###############################################################
#  Generated by:      Cadence Innovus 21.15-s110_1
#  OS:                Linux x86_64(Host ID A17)
#  Generated on:      Sun May  3 01:25:29 2026
#  Design:            Single_Cycle_Core
#  Command:           write_lef_abstract Single_Cycle_Core.lef -5.8
###############################################################

VERSION 5.8 ;

BUSBITCHARS "[]" ;
DIVIDERCHAR "/" ;

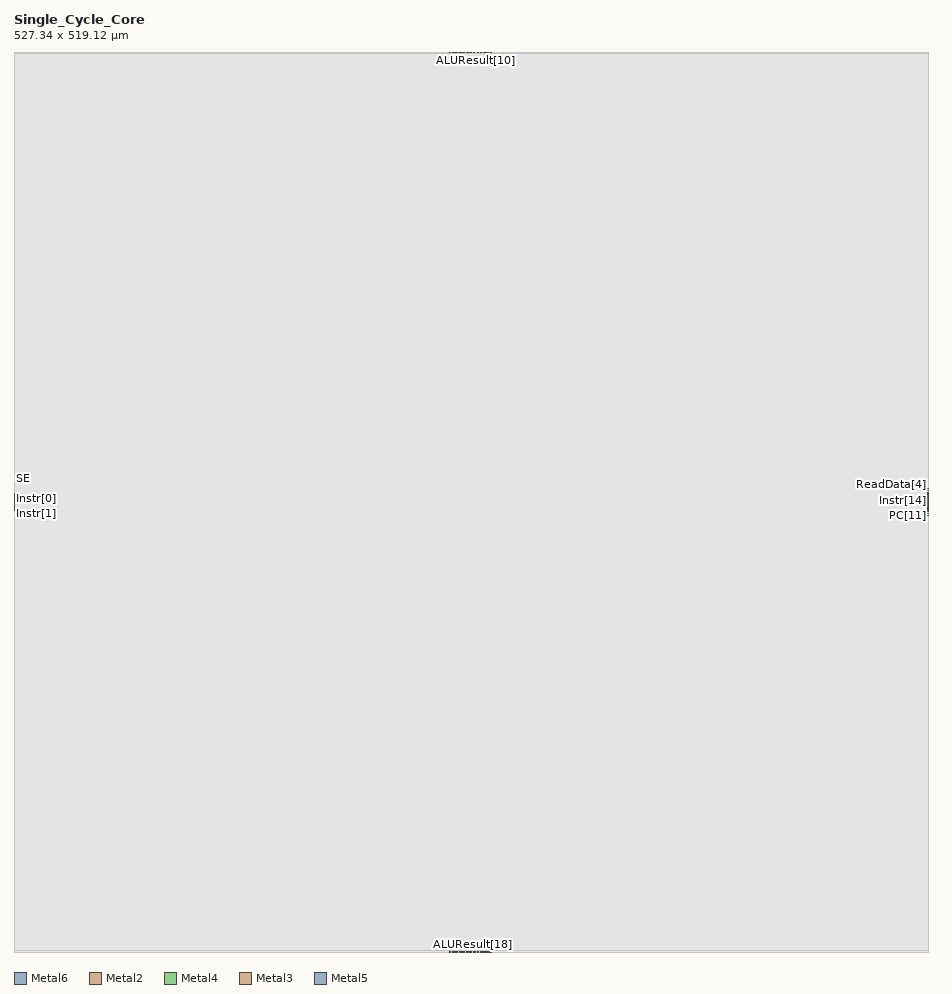
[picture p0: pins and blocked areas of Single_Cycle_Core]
MACRO Single_Cycle_Core
  CLASS BLOCK ;
  SIZE 527.340000 BY 519.120000 ;
  FOREIGN Single_Cycle_Core 0.000000 0.000000 ;
  ORIGIN 0 0 ;
  SYMMETRY X Y R90 ;
  PIN clk
    DIRECTION INPUT ;
    USE SIGNAL ;
    PORT
      LAYER Metal6 ;
        RECT 251.240000 518.680000 251.680000 519.120000 ;
    END
  END clk
  PIN reset
    DIRECTION INPUT ;
    USE SIGNAL ;
    PORT
      LAYER Metal6 ;
        RECT 251.240000 0.000000 251.680000 0.440000 ;
    END
  END reset
  PIN Instr[31]
    DIRECTION INPUT ;
    USE SIGNAL ;
    PORT
      LAYER Metal2 ;
        RECT 259.570000 518.840000 259.850000 519.120000 ;
    END
  END Instr[31]
  PIN Instr[30]
    DIRECTION INPUT ;
    USE SIGNAL ;
    PORT
      LAYER Metal4 ;
        RECT 259.570000 518.840000 259.850000 519.120000 ;
    END
  END Instr[30]
  PIN Instr[29]
    DIRECTION INPUT ;
    USE SIGNAL ;
    PORT
      LAYER Metal2 ;
        RECT 259.570000 0.000000 259.850000 0.280000 ;
    END
  END Instr[29]
  PIN Instr[28]
    DIRECTION INPUT ;
    USE SIGNAL ;
    PORT
      LAYER Metal4 ;
        RECT 259.570000 0.000000 259.850000 0.280000 ;
    END
  END Instr[28]
  PIN Instr[27]
    DIRECTION INPUT ;
    USE SIGNAL ;
    PORT
      LAYER Metal3 ;
        RECT 0.000000 259.420000 0.280000 259.700000 ;
    END
  END Instr[27]
  PIN Instr[26]
    DIRECTION INPUT ;
    USE SIGNAL ;
    PORT
      LAYER Metal5 ;
        RECT 0.000000 259.420000 0.280000 259.700000 ;
    END
  END Instr[26]
  PIN Instr[25]
    DIRECTION INPUT ;
    USE SIGNAL ;
    PORT
      LAYER Metal3 ;
        RECT 527.060000 259.420000 527.340000 259.700000 ;
    END
  END Instr[25]
  PIN Instr[24]
    DIRECTION INPUT ;
    USE SIGNAL ;
    PORT
      LAYER Metal5 ;
        RECT 527.060000 259.420000 527.340000 259.700000 ;
    END
  END Instr[24]
  PIN Instr[23]
    DIRECTION INPUT ;
    USE SIGNAL ;
    PORT
      LAYER Metal6 ;
        RECT 259.160000 518.680000 259.600000 519.120000 ;
    END
  END Instr[23]
  PIN Instr[22]
    DIRECTION INPUT ;
    USE SIGNAL ;
    PORT
      LAYER Metal6 ;
        RECT 259.160000 0.000000 259.600000 0.440000 ;
    END
  END Instr[22]
  PIN Instr[21]
    DIRECTION INPUT ;
    USE SIGNAL ;
    PORT
      LAYER Metal3 ;
        RECT 0.000000 258.300000 0.280000 258.580000 ;
    END
  END Instr[21]
  PIN Instr[20]
    DIRECTION INPUT ;
    USE SIGNAL ;
    PORT
      LAYER Metal3 ;
        RECT 0.000000 260.540000 0.280000 260.820000 ;
    END
  END Instr[20]
  PIN Instr[19]
    DIRECTION INPUT ;
    USE SIGNAL ;
    PORT
      LAYER Metal5 ;
        RECT 0.000000 258.300000 0.280000 258.580000 ;
    END
  END Instr[19]
  PIN Instr[18]
    DIRECTION INPUT ;
    USE SIGNAL ;
    PORT
      LAYER Metal5 ;
        RECT 0.000000 260.540000 0.280000 260.820000 ;
    END
  END Instr[18]
  PIN Instr[17]
    DIRECTION INPUT ;
    USE SIGNAL ;
    PORT
      LAYER Metal3 ;
        RECT 527.060000 258.300000 527.340000 258.580000 ;
    END
  END Instr[17]
  PIN Instr[16]
    DIRECTION INPUT ;
    USE SIGNAL ;
    PORT
      LAYER Metal3 ;
        RECT 527.060000 260.540000 527.340000 260.820000 ;
    END
  END Instr[16]
  PIN Instr[15]
    DIRECTION INPUT ;
    USE SIGNAL ;
    PORT
      LAYER Metal5 ;
        RECT 527.060000 258.300000 527.340000 258.580000 ;
    END
  END Instr[15]
  PIN Instr[14]
    DIRECTION INPUT ;
    USE SIGNAL ;
    PORT
      LAYER Metal5 ;
        RECT 527.060000 260.540000 527.340000 260.820000 ;
    END
  END Instr[14]
  PIN Instr[13]
    DIRECTION INPUT ;
    USE SIGNAL ;
    PORT
      LAYER Metal2 ;
        RECT 258.250000 518.840000 258.530000 519.120000 ;
    END
  END Instr[13]
  PIN Instr[12]
    DIRECTION INPUT ;
    USE SIGNAL ;
    PORT
      LAYER Metal2 ;
        RECT 268.810000 518.840000 269.090000 519.120000 ;
    END
  END Instr[12]
  PIN Instr[11]
    DIRECTION INPUT ;
    USE SIGNAL ;
    PORT
      LAYER Metal4 ;
        RECT 258.250000 518.840000 258.530000 519.120000 ;
    END
  END Instr[11]
  PIN Instr[10]
    DIRECTION INPUT ;
    USE SIGNAL ;
    PORT
      LAYER Metal4 ;
        RECT 268.810000 518.840000 269.090000 519.120000 ;
    END
  END Instr[10]
  PIN Instr[9]
    DIRECTION INPUT ;
    USE SIGNAL ;
    PORT
      LAYER Metal2 ;
        RECT 258.250000 0.000000 258.530000 0.280000 ;
    END
  END Instr[9]
  PIN Instr[8]
    DIRECTION INPUT ;
    USE SIGNAL ;
    PORT
      LAYER Metal2 ;
        RECT 268.810000 0.000000 269.090000 0.280000 ;
    END
  END Instr[8]
  PIN Instr[7]
    DIRECTION INPUT ;
    USE SIGNAL ;
    PORT
      LAYER Metal4 ;
        RECT 258.250000 0.000000 258.530000 0.280000 ;
    END
  END Instr[7]
  PIN Instr[6]
    DIRECTION INPUT ;
    USE SIGNAL ;
    PORT
      LAYER Metal4 ;
        RECT 268.810000 0.000000 269.090000 0.280000 ;
    END
  END Instr[6]
  PIN Instr[5]
    DIRECTION INPUT ;
    USE SIGNAL ;
    PORT
      LAYER Metal6 ;
        RECT 269.060000 518.680000 269.500000 519.120000 ;
    END
  END Instr[5]
  PIN Instr[4]
    DIRECTION INPUT ;
    USE SIGNAL ;
    PORT
      LAYER Metal6 ;
        RECT 269.060000 0.000000 269.500000 0.440000 ;
    END
  END Instr[4]
  PIN Instr[3]
    DIRECTION INPUT ;
    USE SIGNAL ;
    PORT
      LAYER Metal6 ;
        RECT 257.180000 518.680000 257.620000 519.120000 ;
    END
  END Instr[3]
  PIN Instr[2]
    DIRECTION INPUT ;
    USE SIGNAL ;
    PORT
      LAYER Metal6 ;
        RECT 257.180000 0.000000 257.620000 0.440000 ;
    END
  END Instr[2]
  PIN Instr[1]
    DIRECTION INPUT ;
    USE SIGNAL ;
    PORT
      LAYER Metal3 ;
        RECT 0.000000 257.180000 0.280000 257.460000 ;
    END
  END Instr[1]
  PIN Instr[0]
    DIRECTION INPUT ;
    USE SIGNAL ;
    PORT
      LAYER Metal3 ;
        RECT 0.000000 261.660000 0.280000 261.940000 ;
    END
  END Instr[0]
  PIN ReadData[31]
    DIRECTION INPUT ;
    USE SIGNAL ;
    PORT
      LAYER Metal6 ;
        RECT 255.200000 518.680000 255.640000 519.120000 ;
    END
  END ReadData[31]
  PIN ReadData[30]
    DIRECTION INPUT ;
    USE SIGNAL ;
    PORT
      LAYER Metal6 ;
        RECT 255.200000 0.000000 255.640000 0.440000 ;
    END
  END ReadData[30]
  PIN ReadData[29]
    DIRECTION INPUT ;
    USE SIGNAL ;
    PORT
      LAYER Metal3 ;
        RECT 0.000000 254.940000 0.280000 255.220000 ;
    END
  END ReadData[29]
  PIN ReadData[28]
    DIRECTION INPUT ;
    USE SIGNAL ;
    PORT
      LAYER Metal3 ;
        RECT 0.000000 263.900000 0.280000 264.180000 ;
    END
  END ReadData[28]
  PIN ReadData[27]
    DIRECTION INPUT ;
    USE SIGNAL ;
    PORT
      LAYER Metal5 ;
        RECT 0.000000 254.940000 0.280000 255.220000 ;
    END
  END ReadData[27]
  PIN ReadData[26]
    DIRECTION INPUT ;
    USE SIGNAL ;
    PORT
      LAYER Metal5 ;
        RECT 0.000000 263.900000 0.280000 264.180000 ;
    END
  END ReadData[26]
  PIN ReadData[25]
    DIRECTION INPUT ;
    USE SIGNAL ;
    PORT
      LAYER Metal3 ;
        RECT 527.060000 254.940000 527.340000 255.220000 ;
    END
  END ReadData[25]
  PIN ReadData[24]
    DIRECTION INPUT ;
    USE SIGNAL ;
    PORT
      LAYER Metal3 ;
        RECT 527.060000 263.900000 527.340000 264.180000 ;
    END
  END ReadData[24]
  PIN ReadData[23]
    DIRECTION INPUT ;
    USE SIGNAL ;
    PORT
      LAYER Metal5 ;
        RECT 527.060000 254.940000 527.340000 255.220000 ;
    END
  END ReadData[23]
  PIN ReadData[22]
    DIRECTION INPUT ;
    USE SIGNAL ;
    PORT
      LAYER Metal5 ;
        RECT 527.060000 263.900000 527.340000 264.180000 ;
    END
  END ReadData[22]
  PIN ReadData[21]
    DIRECTION INPUT ;
    USE SIGNAL ;
    PORT
      LAYER Metal2 ;
        RECT 254.290000 518.840000 254.570000 519.120000 ;
    END
  END ReadData[21]
  PIN ReadData[20]
    DIRECTION INPUT ;
    USE SIGNAL ;
    PORT
      LAYER Metal2 ;
        RECT 272.770000 518.840000 273.050000 519.120000 ;
    END
  END ReadData[20]
  PIN ReadData[19]
    DIRECTION INPUT ;
    USE SIGNAL ;
    PORT
      LAYER Metal4 ;
        RECT 254.290000 518.840000 254.570000 519.120000 ;
    END
  END ReadData[19]
  PIN ReadData[18]
    DIRECTION INPUT ;
    USE SIGNAL ;
    PORT
      LAYER Metal4 ;
        RECT 272.770000 518.840000 273.050000 519.120000 ;
    END
  END ReadData[18]
  PIN ReadData[17]
    DIRECTION INPUT ;
    USE SIGNAL ;
    PORT
      LAYER Metal2 ;
        RECT 254.290000 0.000000 254.570000 0.280000 ;
    END
  END ReadData[17]
  PIN ReadData[16]
    DIRECTION INPUT ;
    USE SIGNAL ;
    PORT
      LAYER Metal2 ;
        RECT 272.770000 0.000000 273.050000 0.280000 ;
    END
  END ReadData[16]
  PIN ReadData[15]
    DIRECTION INPUT ;
    USE SIGNAL ;
    PORT
      LAYER Metal4 ;
        RECT 254.290000 0.000000 254.570000 0.280000 ;
    END
  END ReadData[15]
  PIN ReadData[14]
    DIRECTION INPUT ;
    USE SIGNAL ;
    PORT
      LAYER Metal4 ;
        RECT 272.770000 0.000000 273.050000 0.280000 ;
    END
  END ReadData[14]
  PIN ReadData[13]
    DIRECTION INPUT ;
    USE SIGNAL ;
    PORT
      LAYER Metal6 ;
        RECT 273.020000 518.680000 273.460000 519.120000 ;
    END
  END ReadData[13]
  PIN ReadData[12]
    DIRECTION INPUT ;
    USE SIGNAL ;
    PORT
      LAYER Metal6 ;
        RECT 273.020000 0.000000 273.460000 0.440000 ;
    END
  END ReadData[12]
  PIN ReadData[11]
    DIRECTION INPUT ;
    USE SIGNAL ;
    PORT
      LAYER Metal3 ;
        RECT 0.000000 253.820000 0.280000 254.100000 ;
    END
  END ReadData[11]
  PIN ReadData[10]
    DIRECTION INPUT ;
    USE SIGNAL ;
    PORT
      LAYER Metal3 ;
        RECT 0.000000 265.020000 0.280000 265.300000 ;
    END
  END ReadData[10]
  PIN ReadData[9]
    DIRECTION INPUT ;
    USE SIGNAL ;
    PORT
      LAYER Metal5 ;
        RECT 0.000000 253.820000 0.280000 254.100000 ;
    END
  END ReadData[9]
  PIN ReadData[8]
    DIRECTION INPUT ;
    USE SIGNAL ;
    PORT
      LAYER Metal5 ;
        RECT 0.000000 265.020000 0.280000 265.300000 ;
    END
  END ReadData[8]
  PIN ReadData[7]
    DIRECTION INPUT ;
    USE SIGNAL ;
    PORT
      LAYER Metal3 ;
        RECT 527.060000 253.820000 527.340000 254.100000 ;
    END
  END ReadData[7]
  PIN ReadData[6]
    DIRECTION INPUT ;
    USE SIGNAL ;
    PORT
      LAYER Metal3 ;
        RECT 527.060000 265.020000 527.340000 265.300000 ;
    END
  END ReadData[6]
  PIN ReadData[5]
    DIRECTION INPUT ;
    USE SIGNAL ;
    PORT
      LAYER Metal5 ;
        RECT 527.060000 253.820000 527.340000 254.100000 ;
    END
  END ReadData[5]
  PIN ReadData[4]
    DIRECTION INPUT ;
    USE SIGNAL ;
    PORT
      LAYER Metal5 ;
        RECT 527.060000 265.020000 527.340000 265.300000 ;
    END
  END ReadData[4]
  PIN ReadData[3]
    DIRECTION INPUT ;
    USE SIGNAL ;
    PORT
      LAYER Metal6 ;
        RECT 253.220000 518.680000 253.660000 519.120000 ;
    END
  END ReadData[3]
  PIN ReadData[2]
    DIRECTION INPUT ;
    USE SIGNAL ;
    PORT
      LAYER Metal6 ;
        RECT 253.220000 0.000000 253.660000 0.440000 ;
    END
  END ReadData[2]
  PIN ReadData[1]
    DIRECTION INPUT ;
    USE SIGNAL ;
    PORT
      LAYER Metal2 ;
        RECT 252.970000 518.840000 253.250000 519.120000 ;
    END
  END ReadData[1]
  PIN ReadData[0]
    DIRECTION INPUT ;
    USE SIGNAL ;
    PORT
      LAYER Metal2 ;
        RECT 274.090000 518.840000 274.370000 519.120000 ;
    END
  END ReadData[0]
  PIN PC[31]
    DIRECTION OUTPUT ;
    USE SIGNAL ;
    PORT
      LAYER Metal5 ;
        RECT 0.000000 257.180000 0.280000 257.460000 ;
    END
  END PC[31]
  PIN PC[30]
    DIRECTION OUTPUT ;
    USE SIGNAL ;
    PORT
      LAYER Metal5 ;
        RECT 0.000000 261.660000 0.280000 261.940000 ;
    END
  END PC[30]
  PIN PC[29]
    DIRECTION OUTPUT ;
    USE SIGNAL ;
    PORT
      LAYER Metal3 ;
        RECT 527.060000 257.180000 527.340000 257.460000 ;
    END
  END PC[29]
  PIN PC[28]
    DIRECTION OUTPUT ;
    USE SIGNAL ;
    PORT
      LAYER Metal3 ;
        RECT 527.060000 261.660000 527.340000 261.940000 ;
    END
  END PC[28]
  PIN PC[27]
    DIRECTION OUTPUT ;
    USE SIGNAL ;
    PORT
      LAYER Metal5 ;
        RECT 527.060000 257.180000 527.340000 257.460000 ;
    END
  END PC[27]
  PIN PC[26]
    DIRECTION OUTPUT ;
    USE SIGNAL ;
    PORT
      LAYER Metal5 ;
        RECT 527.060000 261.660000 527.340000 261.940000 ;
    END
  END PC[26]
  PIN PC[25]
    DIRECTION OUTPUT ;
    USE SIGNAL ;
    PORT
      LAYER Metal2 ;
        RECT 256.930000 518.840000 257.210000 519.120000 ;
    END
  END PC[25]
  PIN PC[24]
    DIRECTION OUTPUT ;
    USE SIGNAL ;
    PORT
      LAYER Metal2 ;
        RECT 270.130000 518.840000 270.410000 519.120000 ;
    END
  END PC[24]
  PIN PC[23]
    DIRECTION OUTPUT ;
    USE SIGNAL ;
    PORT
      LAYER Metal4 ;
        RECT 256.930000 518.840000 257.210000 519.120000 ;
    END
  END PC[23]
  PIN PC[22]
    DIRECTION OUTPUT ;
    USE SIGNAL ;
    PORT
      LAYER Metal4 ;
        RECT 270.130000 518.840000 270.410000 519.120000 ;
    END
  END PC[22]
  PIN PC[21]
    DIRECTION OUTPUT ;
    USE SIGNAL ;
    PORT
      LAYER Metal2 ;
        RECT 256.930000 0.000000 257.210000 0.280000 ;
    END
  END PC[21]
  PIN PC[20]
    DIRECTION OUTPUT ;
    USE SIGNAL ;
    PORT
      LAYER Metal2 ;
        RECT 270.130000 0.000000 270.410000 0.280000 ;
    END
  END PC[20]
  PIN PC[19]
    DIRECTION OUTPUT ;
    USE SIGNAL ;
    PORT
      LAYER Metal4 ;
        RECT 256.930000 0.000000 257.210000 0.280000 ;
    END
  END PC[19]
  PIN PC[18]
    DIRECTION OUTPUT ;
    USE SIGNAL ;
    PORT
      LAYER Metal4 ;
        RECT 270.130000 0.000000 270.410000 0.280000 ;
    END
  END PC[18]
  PIN PC[17]
    DIRECTION OUTPUT ;
    USE SIGNAL ;
    PORT
      LAYER Metal3 ;
        RECT 0.000000 256.060000 0.280000 256.340000 ;
    END
  END PC[17]
  PIN PC[16]
    DIRECTION OUTPUT ;
    USE SIGNAL ;
    PORT
      LAYER Metal3 ;
        RECT 0.000000 262.780000 0.280000 263.060000 ;
    END
  END PC[16]
  PIN PC[15]
    DIRECTION OUTPUT ;
    USE SIGNAL ;
    PORT
      LAYER Metal5 ;
        RECT 0.000000 256.060000 0.280000 256.340000 ;
    END
  END PC[15]
  PIN PC[14]
    DIRECTION OUTPUT ;
    USE SIGNAL ;
    PORT
      LAYER Metal5 ;
        RECT 0.000000 262.780000 0.280000 263.060000 ;
    END
  END PC[14]
  PIN PC[13]
    DIRECTION OUTPUT ;
    USE SIGNAL ;
    PORT
      LAYER Metal3 ;
        RECT 527.060000 256.060000 527.340000 256.340000 ;
    END
  END PC[13]
  PIN PC[12]
    DIRECTION OUTPUT ;
    USE SIGNAL ;
    PORT
      LAYER Metal3 ;
        RECT 527.060000 262.780000 527.340000 263.060000 ;
    END
  END PC[12]
  PIN PC[11]
    DIRECTION OUTPUT ;
    USE SIGNAL ;
    PORT
      LAYER Metal5 ;
        RECT 527.060000 256.060000 527.340000 256.340000 ;
    END
  END PC[11]
  PIN PC[10]
    DIRECTION OUTPUT ;
    USE SIGNAL ;
    PORT
      LAYER Metal5 ;
        RECT 527.060000 262.780000 527.340000 263.060000 ;
    END
  END PC[10]
  PIN PC[9]
    DIRECTION OUTPUT ;
    USE SIGNAL ;
    PORT
      LAYER Metal2 ;
        RECT 271.450000 518.840000 271.730000 519.120000 ;
    END
  END PC[9]
  PIN PC[8]
    DIRECTION OUTPUT ;
    USE SIGNAL ;
    PORT
      LAYER Metal4 ;
        RECT 271.450000 518.840000 271.730000 519.120000 ;
    END
  END PC[8]
  PIN PC[7]
    DIRECTION OUTPUT ;
    USE SIGNAL ;
    PORT
      LAYER Metal6 ;
        RECT 271.040000 518.680000 271.480000 519.120000 ;
    END
  END PC[7]
  PIN PC[6]
    DIRECTION OUTPUT ;
    USE SIGNAL ;
    PORT
      LAYER Metal2 ;
        RECT 271.450000 0.000000 271.730000 0.280000 ;
    END
  END PC[6]
  PIN PC[5]
    DIRECTION OUTPUT ;
    USE SIGNAL ;
    PORT
      LAYER Metal4 ;
        RECT 271.450000 0.000000 271.730000 0.280000 ;
    END
  END PC[5]
  PIN PC[4]
    DIRECTION OUTPUT ;
    USE SIGNAL ;
    PORT
      LAYER Metal6 ;
        RECT 271.040000 0.000000 271.480000 0.440000 ;
    END
  END PC[4]
  PIN PC[3]
    DIRECTION OUTPUT ;
    USE SIGNAL ;
    PORT
      LAYER Metal2 ;
        RECT 255.610000 518.840000 255.890000 519.120000 ;
    END
  END PC[3]
  PIN PC[2]
    DIRECTION OUTPUT ;
    USE SIGNAL ;
    PORT
      LAYER Metal4 ;
        RECT 255.610000 518.840000 255.890000 519.120000 ;
    END
  END PC[2]
  PIN PC[1]
    DIRECTION OUTPUT ;
    USE SIGNAL ;
    PORT
      LAYER Metal2 ;
        RECT 255.610000 0.000000 255.890000 0.280000 ;
    END
  END PC[1]
  PIN PC[0]
    DIRECTION OUTPUT ;
    USE SIGNAL ;
    PORT
      LAYER Metal4 ;
        RECT 255.610000 0.000000 255.890000 0.280000 ;
    END
  END PC[0]
  PIN MemWrite
    DIRECTION OUTPUT ;
    USE SIGNAL ;
    PORT
      LAYER Metal3 ;
        RECT 0.000000 250.460000 0.280000 250.740000 ;
    END
  END MemWrite
  PIN ALUResult[31]
    DIRECTION OUTPUT ;
    USE SIGNAL ;
    PORT
      LAYER Metal2 ;
        RECT 263.530000 518.840000 263.810000 519.120000 ;
    END
  END ALUResult[31]
  PIN ALUResult[30]
    DIRECTION OUTPUT ;
    USE SIGNAL ;
    PORT
      LAYER Metal4 ;
        RECT 263.530000 518.840000 263.810000 519.120000 ;
    END
  END ALUResult[30]
  PIN ALUResult[29]
    DIRECTION OUTPUT ;
    USE SIGNAL ;
    PORT
      LAYER Metal2 ;
        RECT 263.530000 0.000000 263.810000 0.280000 ;
    END
  END ALUResult[29]
  PIN ALUResult[28]
    DIRECTION OUTPUT ;
    USE SIGNAL ;
    PORT
      LAYER Metal4 ;
        RECT 263.530000 0.000000 263.810000 0.280000 ;
    END
  END ALUResult[28]
  PIN ALUResult[27]
    DIRECTION OUTPUT ;
    USE SIGNAL ;
    PORT
      LAYER Metal6 ;
        RECT 263.120000 518.680000 263.560000 519.120000 ;
    END
  END ALUResult[27]
  PIN ALUResult[26]
    DIRECTION OUTPUT ;
    USE SIGNAL ;
    PORT
      LAYER Metal6 ;
        RECT 263.120000 0.000000 263.560000 0.440000 ;
    END
  END ALUResult[26]
  PIN ALUResult[25]
    DIRECTION OUTPUT ;
    USE SIGNAL ;
    PORT
      LAYER Metal2 ;
        RECT 262.210000 518.840000 262.490000 519.120000 ;
    END
  END ALUResult[25]
  PIN ALUResult[24]
    DIRECTION OUTPUT ;
    USE SIGNAL ;
    PORT
      LAYER Metal2 ;
        RECT 264.850000 518.840000 265.130000 519.120000 ;
    END
  END ALUResult[24]
  PIN ALUResult[23]
    DIRECTION OUTPUT ;
    USE SIGNAL ;
    PORT
      LAYER Metal4 ;
        RECT 262.210000 518.840000 262.490000 519.120000 ;
    END
  END ALUResult[23]
  PIN ALUResult[22]
    DIRECTION OUTPUT ;
    USE SIGNAL ;
    PORT
      LAYER Metal4 ;
        RECT 264.850000 518.840000 265.130000 519.120000 ;
    END
  END ALUResult[22]
  PIN ALUResult[21]
    DIRECTION OUTPUT ;
    USE SIGNAL ;
    PORT
      LAYER Metal2 ;
        RECT 262.210000 0.000000 262.490000 0.280000 ;
    END
  END ALUResult[21]
  PIN ALUResult[20]
    DIRECTION OUTPUT ;
    USE SIGNAL ;
    PORT
      LAYER Metal2 ;
        RECT 264.850000 0.000000 265.130000 0.280000 ;
    END
  END ALUResult[20]
  PIN ALUResult[19]
    DIRECTION OUTPUT ;
    USE SIGNAL ;
    PORT
      LAYER Metal4 ;
        RECT 262.210000 0.000000 262.490000 0.280000 ;
    END
  END ALUResult[19]
  PIN ALUResult[18]
    DIRECTION OUTPUT ;
    USE SIGNAL ;
    PORT
      LAYER Metal4 ;
        RECT 264.850000 0.000000 265.130000 0.280000 ;
    END
  END ALUResult[18]
  PIN ALUResult[17]
    DIRECTION OUTPUT ;
    USE SIGNAL ;
    PORT
      LAYER Metal6 ;
        RECT 265.100000 518.680000 265.540000 519.120000 ;
    END
  END ALUResult[17]
  PIN ALUResult[16]
    DIRECTION OUTPUT ;
    USE SIGNAL ;
    PORT
      LAYER Metal6 ;
        RECT 265.100000 0.000000 265.540000 0.440000 ;
    END
  END ALUResult[16]
  PIN ALUResult[15]
    DIRECTION OUTPUT ;
    USE SIGNAL ;
    PORT
      LAYER Metal6 ;
        RECT 261.140000 518.680000 261.580000 519.120000 ;
    END
  END ALUResult[15]
  PIN ALUResult[14]
    DIRECTION OUTPUT ;
    USE SIGNAL ;
    PORT
      LAYER Metal6 ;
        RECT 261.140000 0.000000 261.580000 0.440000 ;
    END
  END ALUResult[14]
  PIN ALUResult[13]
    DIRECTION OUTPUT ;
    USE SIGNAL ;
    PORT
      LAYER Metal2 ;
        RECT 260.890000 518.840000 261.170000 519.120000 ;
    END
  END ALUResult[13]
  PIN ALUResult[12]
    DIRECTION OUTPUT ;
    USE SIGNAL ;
    PORT
      LAYER Metal2 ;
        RECT 266.170000 518.840000 266.450000 519.120000 ;
    END
  END ALUResult[12]
  PIN ALUResult[11]
    DIRECTION OUTPUT ;
    USE SIGNAL ;
    PORT
      LAYER Metal4 ;
        RECT 260.890000 518.840000 261.170000 519.120000 ;
    END
  END ALUResult[11]
  PIN ALUResult[10]
    DIRECTION OUTPUT ;
    USE SIGNAL ;
    PORT
      LAYER Metal4 ;
        RECT 266.170000 518.840000 266.450000 519.120000 ;
    END
  END ALUResult[10]
  PIN ALUResult[9]
    DIRECTION OUTPUT ;
    USE SIGNAL ;
    PORT
      LAYER Metal2 ;
        RECT 260.890000 0.000000 261.170000 0.280000 ;
    END
  END ALUResult[9]
  PIN ALUResult[8]
    DIRECTION OUTPUT ;
    USE SIGNAL ;
    PORT
      LAYER Metal2 ;
        RECT 266.170000 0.000000 266.450000 0.280000 ;
    END
  END ALUResult[8]
  PIN ALUResult[7]
    DIRECTION OUTPUT ;
    USE SIGNAL ;
    PORT
      LAYER Metal4 ;
        RECT 260.890000 0.000000 261.170000 0.280000 ;
    END
  END ALUResult[7]
  PIN ALUResult[6]
    DIRECTION OUTPUT ;
    USE SIGNAL ;
    PORT
      LAYER Metal4 ;
        RECT 266.170000 0.000000 266.450000 0.280000 ;
    END
  END ALUResult[6]
  PIN ALUResult[5]
    DIRECTION OUTPUT ;
    USE SIGNAL ;
    PORT
      LAYER Metal2 ;
        RECT 267.490000 518.840000 267.770000 519.120000 ;
    END
  END ALUResult[5]
  PIN ALUResult[4]
    DIRECTION OUTPUT ;
    USE SIGNAL ;
    PORT
      LAYER Metal4 ;
        RECT 267.490000 518.840000 267.770000 519.120000 ;
    END
  END ALUResult[4]
  PIN ALUResult[3]
    DIRECTION OUTPUT ;
    USE SIGNAL ;
    PORT
      LAYER Metal6 ;
        RECT 267.080000 518.680000 267.520000 519.120000 ;
    END
  END ALUResult[3]
  PIN ALUResult[2]
    DIRECTION OUTPUT ;
    USE SIGNAL ;
    PORT
      LAYER Metal2 ;
        RECT 267.490000 0.000000 267.770000 0.280000 ;
    END
  END ALUResult[2]
  PIN ALUResult[1]
    DIRECTION OUTPUT ;
    USE SIGNAL ;
    PORT
      LAYER Metal4 ;
        RECT 267.490000 0.000000 267.770000 0.280000 ;
    END
  END ALUResult[1]
  PIN ALUResult[0]
    DIRECTION OUTPUT ;
    USE SIGNAL ;
    PORT
      LAYER Metal6 ;
        RECT 267.080000 0.000000 267.520000 0.440000 ;
    END
  END ALUResult[0]
  PIN WriteData[31]
    DIRECTION OUTPUT ;
    USE SIGNAL ;
    PORT
      LAYER Metal4 ;
        RECT 252.970000 518.840000 253.250000 519.120000 ;
    END
  END WriteData[31]
  PIN WriteData[30]
    DIRECTION OUTPUT ;
    USE SIGNAL ;
    PORT
      LAYER Metal4 ;
        RECT 274.090000 518.840000 274.370000 519.120000 ;
    END
  END WriteData[30]
  PIN WriteData[29]
    DIRECTION OUTPUT ;
    USE SIGNAL ;
    PORT
      LAYER Metal2 ;
        RECT 252.970000 0.000000 253.250000 0.280000 ;
    END
  END WriteData[29]
  PIN WriteData[28]
    DIRECTION OUTPUT ;
    USE SIGNAL ;
    PORT
      LAYER Metal2 ;
        RECT 274.090000 0.000000 274.370000 0.280000 ;
    END
  END WriteData[28]
  PIN WriteData[27]
    DIRECTION OUTPUT ;
    USE SIGNAL ;
    PORT
      LAYER Metal4 ;
        RECT 252.970000 0.000000 253.250000 0.280000 ;
    END
  END WriteData[27]
  PIN WriteData[26]
    DIRECTION OUTPUT ;
    USE SIGNAL ;
    PORT
      LAYER Metal4 ;
        RECT 274.090000 0.000000 274.370000 0.280000 ;
    END
  END WriteData[26]
  PIN WriteData[25]
    DIRECTION OUTPUT ;
    USE SIGNAL ;
    PORT
      LAYER Metal3 ;
        RECT 0.000000 252.700000 0.280000 252.980000 ;
    END
  END WriteData[25]
  PIN WriteData[24]
    DIRECTION OUTPUT ;
    USE SIGNAL ;
    PORT
      LAYER Metal3 ;
        RECT 0.000000 266.140000 0.280000 266.420000 ;
    END
  END WriteData[24]
  PIN WriteData[23]
    DIRECTION OUTPUT ;
    USE SIGNAL ;
    PORT
      LAYER Metal5 ;
        RECT 0.000000 252.700000 0.280000 252.980000 ;
    END
  END WriteData[23]
  PIN WriteData[22]
    DIRECTION OUTPUT ;
    USE SIGNAL ;
    PORT
      LAYER Metal5 ;
        RECT 0.000000 266.140000 0.280000 266.420000 ;
    END
  END WriteData[22]
  PIN WriteData[21]
    DIRECTION OUTPUT ;
    USE SIGNAL ;
    PORT
      LAYER Metal3 ;
        RECT 527.060000 252.700000 527.340000 252.980000 ;
    END
  END WriteData[21]
  PIN WriteData[20]
    DIRECTION OUTPUT ;
    USE SIGNAL ;
    PORT
      LAYER Metal3 ;
        RECT 527.060000 266.140000 527.340000 266.420000 ;
    END
  END WriteData[20]
  PIN WriteData[19]
    DIRECTION OUTPUT ;
    USE SIGNAL ;
    PORT
      LAYER Metal5 ;
        RECT 527.060000 252.700000 527.340000 252.980000 ;
    END
  END WriteData[19]
  PIN WriteData[18]
    DIRECTION OUTPUT ;
    USE SIGNAL ;
    PORT
      LAYER Metal5 ;
        RECT 527.060000 266.140000 527.340000 266.420000 ;
    END
  END WriteData[18]
  PIN WriteData[17]
    DIRECTION OUTPUT ;
    USE SIGNAL ;
    PORT
      LAYER Metal2 ;
        RECT 275.410000 518.840000 275.690000 519.120000 ;
    END
  END WriteData[17]
  PIN WriteData[16]
    DIRECTION OUTPUT ;
    USE SIGNAL ;
    PORT
      LAYER Metal4 ;
        RECT 275.410000 518.840000 275.690000 519.120000 ;
    END
  END WriteData[16]
  PIN WriteData[15]
    DIRECTION OUTPUT ;
    USE SIGNAL ;
    PORT
      LAYER Metal6 ;
        RECT 275.000000 518.680000 275.440000 519.120000 ;
    END
  END WriteData[15]
  PIN WriteData[14]
    DIRECTION OUTPUT ;
    USE SIGNAL ;
    PORT
      LAYER Metal2 ;
        RECT 275.410000 0.000000 275.690000 0.280000 ;
    END
  END WriteData[14]
  PIN WriteData[13]
    DIRECTION OUTPUT ;
    USE SIGNAL ;
    PORT
      LAYER Metal4 ;
        RECT 275.410000 0.000000 275.690000 0.280000 ;
    END
  END WriteData[13]
  PIN WriteData[12]
    DIRECTION OUTPUT ;
    USE SIGNAL ;
    PORT
      LAYER Metal6 ;
        RECT 275.000000 0.000000 275.440000 0.440000 ;
    END
  END WriteData[12]
  PIN WriteData[11]
    DIRECTION OUTPUT ;
    USE SIGNAL ;
    PORT
      LAYER Metal2 ;
        RECT 251.650000 518.840000 251.930000 519.120000 ;
    END
  END WriteData[11]
  PIN WriteData[10]
    DIRECTION OUTPUT ;
    USE SIGNAL ;
    PORT
      LAYER Metal4 ;
        RECT 251.650000 518.840000 251.930000 519.120000 ;
    END
  END WriteData[10]
  PIN WriteData[9]
    DIRECTION OUTPUT ;
    USE SIGNAL ;
    PORT
      LAYER Metal2 ;
        RECT 251.650000 0.000000 251.930000 0.280000 ;
    END
  END WriteData[9]
  PIN WriteData[8]
    DIRECTION OUTPUT ;
    USE SIGNAL ;
    PORT
      LAYER Metal4 ;
        RECT 251.650000 0.000000 251.930000 0.280000 ;
    END
  END WriteData[8]
  PIN WriteData[7]
    DIRECTION OUTPUT ;
    USE SIGNAL ;
    PORT
      LAYER Metal3 ;
        RECT 0.000000 251.580000 0.280000 251.860000 ;
    END
  END WriteData[7]
  PIN WriteData[6]
    DIRECTION OUTPUT ;
    USE SIGNAL ;
    PORT
      LAYER Metal3 ;
        RECT 0.000000 267.260000 0.280000 267.540000 ;
    END
  END WriteData[6]
  PIN WriteData[5]
    DIRECTION OUTPUT ;
    USE SIGNAL ;
    PORT
      LAYER Metal5 ;
        RECT 0.000000 251.580000 0.280000 251.860000 ;
    END
  END WriteData[5]
  PIN WriteData[4]
    DIRECTION OUTPUT ;
    USE SIGNAL ;
    PORT
      LAYER Metal5 ;
        RECT 0.000000 267.260000 0.280000 267.540000 ;
    END
  END WriteData[4]
  PIN WriteData[3]
    DIRECTION OUTPUT ;
    USE SIGNAL ;
    PORT
      LAYER Metal3 ;
        RECT 527.060000 251.580000 527.340000 251.860000 ;
    END
  END WriteData[3]
  PIN WriteData[2]
    DIRECTION OUTPUT ;
    USE SIGNAL ;
    PORT
      LAYER Metal3 ;
        RECT 527.060000 267.260000 527.340000 267.540000 ;
    END
  END WriteData[2]
  PIN WriteData[1]
    DIRECTION OUTPUT ;
    USE SIGNAL ;
    PORT
      LAYER Metal5 ;
        RECT 527.060000 251.580000 527.340000 251.860000 ;
    END
  END WriteData[1]
  PIN WriteData[0]
    DIRECTION OUTPUT ;
    USE SIGNAL ;
    PORT
      LAYER Metal5 ;
        RECT 527.060000 267.260000 527.340000 267.540000 ;
    END
  END WriteData[0]
  PIN SE
    DIRECTION INPUT ;
    USE SIGNAL ;
    PORT
      LAYER Metal3 ;
        RECT 0.000000 268.380000 0.280000 268.660000 ;
    END
  END SE
  PIN scan_in
    DIRECTION INPUT ;
    USE SIGNAL ;
    PORT
      LAYER Metal5 ;
        RECT 0.000000 250.460000 0.280000 250.740000 ;
    END
  END scan_in
  PIN scan_out
    DIRECTION OUTPUT ;
    USE SIGNAL ;
    PORT
      LAYER Metal5 ;
        RECT 0.000000 268.380000 0.280000 268.660000 ;
    END
  END scan_out
  OBS
    LAYER Metal1 ;
      RECT 0.000000 0.000000 527.340000 519.120000 ;
    LAYER Metal2 ;
      RECT 275.970000 518.560000 527.340000 519.120000 ;
      RECT 274.650000 518.560000 275.130000 519.120000 ;
      RECT 273.330000 518.560000 273.810000 519.120000 ;
      RECT 272.010000 518.560000 272.490000 519.120000 ;
      RECT 270.690000 518.560000 271.170000 519.120000 ;
      RECT 269.370000 518.560000 269.850000 519.120000 ;
      RECT 268.050000 518.560000 268.530000 519.120000 ;
      RECT 266.730000 518.560000 267.210000 519.120000 ;
      RECT 265.410000 518.560000 265.890000 519.120000 ;
      RECT 264.090000 518.560000 264.570000 519.120000 ;
      RECT 262.770000 518.560000 263.250000 519.120000 ;
      RECT 261.450000 518.560000 261.930000 519.120000 ;
      RECT 260.130000 518.560000 260.610000 519.120000 ;
      RECT 258.810000 518.560000 259.290000 519.120000 ;
      RECT 257.490000 518.560000 257.970000 519.120000 ;
      RECT 256.170000 518.560000 256.650000 519.120000 ;
      RECT 254.850000 518.560000 255.330000 519.120000 ;
      RECT 253.530000 518.560000 254.010000 519.120000 ;
      RECT 252.210000 518.560000 252.690000 519.120000 ;
      RECT 0.000000 518.560000 251.370000 519.120000 ;
      RECT 0.000000 0.560000 527.340000 518.560000 ;
      RECT 275.970000 0.000000 527.340000 0.560000 ;
      RECT 274.650000 0.000000 275.130000 0.560000 ;
      RECT 273.330000 0.000000 273.810000 0.560000 ;
      RECT 272.010000 0.000000 272.490000 0.560000 ;
      RECT 270.690000 0.000000 271.170000 0.560000 ;
      RECT 269.370000 0.000000 269.850000 0.560000 ;
      RECT 268.050000 0.000000 268.530000 0.560000 ;
      RECT 266.730000 0.000000 267.210000 0.560000 ;
      RECT 265.410000 0.000000 265.890000 0.560000 ;
      RECT 264.090000 0.000000 264.570000 0.560000 ;
      RECT 262.770000 0.000000 263.250000 0.560000 ;
      RECT 261.450000 0.000000 261.930000 0.560000 ;
      RECT 260.130000 0.000000 260.610000 0.560000 ;
      RECT 258.810000 0.000000 259.290000 0.560000 ;
      RECT 257.490000 0.000000 257.970000 0.560000 ;
      RECT 256.170000 0.000000 256.650000 0.560000 ;
      RECT 254.850000 0.000000 255.330000 0.560000 ;
      RECT 253.530000 0.000000 254.010000 0.560000 ;
      RECT 252.210000 0.000000 252.690000 0.560000 ;
      RECT 0.000000 0.000000 251.370000 0.560000 ;
    LAYER Metal3 ;
      RECT 0.000000 268.940000 527.340000 519.120000 ;
      RECT 0.560000 268.100000 527.340000 268.940000 ;
      RECT 0.000000 267.820000 527.340000 268.100000 ;
      RECT 0.560000 266.980000 526.780000 267.820000 ;
      RECT 0.000000 266.700000 527.340000 266.980000 ;
      RECT 0.560000 265.860000 526.780000 266.700000 ;
      RECT 0.000000 265.580000 527.340000 265.860000 ;
      RECT 0.560000 264.740000 526.780000 265.580000 ;
      RECT 0.000000 264.460000 527.340000 264.740000 ;
      RECT 0.560000 263.620000 526.780000 264.460000 ;
      RECT 0.000000 263.340000 527.340000 263.620000 ;
      RECT 0.560000 262.500000 526.780000 263.340000 ;
      RECT 0.000000 262.220000 527.340000 262.500000 ;
      RECT 0.560000 261.380000 526.780000 262.220000 ;
      RECT 0.000000 261.100000 527.340000 261.380000 ;
      RECT 0.560000 260.260000 526.780000 261.100000 ;
      RECT 0.000000 259.980000 527.340000 260.260000 ;
      RECT 0.560000 259.140000 526.780000 259.980000 ;
      RECT 0.000000 258.860000 527.340000 259.140000 ;
      RECT 0.560000 258.020000 526.780000 258.860000 ;
      RECT 0.000000 257.740000 527.340000 258.020000 ;
      RECT 0.560000 256.900000 526.780000 257.740000 ;
      RECT 0.000000 256.620000 527.340000 256.900000 ;
      RECT 0.560000 255.780000 526.780000 256.620000 ;
      RECT 0.000000 255.500000 527.340000 255.780000 ;
      RECT 0.560000 254.660000 526.780000 255.500000 ;
      RECT 0.000000 254.380000 527.340000 254.660000 ;
      RECT 0.560000 253.540000 526.780000 254.380000 ;
      RECT 0.000000 253.260000 527.340000 253.540000 ;
      RECT 0.560000 252.420000 526.780000 253.260000 ;
      RECT 0.000000 252.140000 527.340000 252.420000 ;
      RECT 0.560000 251.300000 526.780000 252.140000 ;
      RECT 0.000000 251.020000 527.340000 251.300000 ;
      RECT 0.560000 250.180000 527.340000 251.020000 ;
      RECT 0.000000 0.000000 527.340000 250.180000 ;
    LAYER Metal4 ;
      RECT 275.970000 518.560000 527.340000 519.120000 ;
      RECT 274.650000 518.560000 275.130000 519.120000 ;
      RECT 273.330000 518.560000 273.810000 519.120000 ;
      RECT 272.010000 518.560000 272.490000 519.120000 ;
      RECT 270.690000 518.560000 271.170000 519.120000 ;
      RECT 269.370000 518.560000 269.850000 519.120000 ;
      RECT 268.050000 518.560000 268.530000 519.120000 ;
      RECT 266.730000 518.560000 267.210000 519.120000 ;
      RECT 265.410000 518.560000 265.890000 519.120000 ;
      RECT 264.090000 518.560000 264.570000 519.120000 ;
      RECT 262.770000 518.560000 263.250000 519.120000 ;
      RECT 261.450000 518.560000 261.930000 519.120000 ;
      RECT 260.130000 518.560000 260.610000 519.120000 ;
      RECT 258.810000 518.560000 259.290000 519.120000 ;
      RECT 257.490000 518.560000 257.970000 519.120000 ;
      RECT 256.170000 518.560000 256.650000 519.120000 ;
      RECT 254.850000 518.560000 255.330000 519.120000 ;
      RECT 253.530000 518.560000 254.010000 519.120000 ;
      RECT 252.210000 518.560000 252.690000 519.120000 ;
      RECT 0.000000 518.560000 251.370000 519.120000 ;
      RECT 0.000000 0.560000 527.340000 518.560000 ;
      RECT 275.970000 0.000000 527.340000 0.560000 ;
      RECT 274.650000 0.000000 275.130000 0.560000 ;
      RECT 273.330000 0.000000 273.810000 0.560000 ;
      RECT 272.010000 0.000000 272.490000 0.560000 ;
      RECT 270.690000 0.000000 271.170000 0.560000 ;
      RECT 269.370000 0.000000 269.850000 0.560000 ;
      RECT 268.050000 0.000000 268.530000 0.560000 ;
      RECT 266.730000 0.000000 267.210000 0.560000 ;
      RECT 265.410000 0.000000 265.890000 0.560000 ;
      RECT 264.090000 0.000000 264.570000 0.560000 ;
      RECT 262.770000 0.000000 263.250000 0.560000 ;
      RECT 261.450000 0.000000 261.930000 0.560000 ;
      RECT 260.130000 0.000000 260.610000 0.560000 ;
      RECT 258.810000 0.000000 259.290000 0.560000 ;
      RECT 257.490000 0.000000 257.970000 0.560000 ;
      RECT 256.170000 0.000000 256.650000 0.560000 ;
      RECT 254.850000 0.000000 255.330000 0.560000 ;
      RECT 253.530000 0.000000 254.010000 0.560000 ;
      RECT 252.210000 0.000000 252.690000 0.560000 ;
      RECT 0.000000 0.000000 251.370000 0.560000 ;
    LAYER Metal5 ;
      RECT 0.000000 268.940000 527.340000 519.120000 ;
      RECT 0.560000 268.100000 527.340000 268.940000 ;
      RECT 0.000000 267.820000 527.340000 268.100000 ;
      RECT 0.560000 266.980000 526.780000 267.820000 ;
      RECT 0.000000 266.700000 527.340000 266.980000 ;
      RECT 0.560000 265.860000 526.780000 266.700000 ;
      RECT 0.000000 265.580000 527.340000 265.860000 ;
      RECT 0.560000 264.740000 526.780000 265.580000 ;
      RECT 0.000000 264.460000 527.340000 264.740000 ;
      RECT 0.560000 263.620000 526.780000 264.460000 ;
      RECT 0.000000 263.340000 527.340000 263.620000 ;
      RECT 0.560000 262.500000 526.780000 263.340000 ;
      RECT 0.000000 262.220000 527.340000 262.500000 ;
      RECT 0.560000 261.380000 526.780000 262.220000 ;
      RECT 0.000000 261.100000 527.340000 261.380000 ;
      RECT 0.560000 260.260000 526.780000 261.100000 ;
      RECT 0.000000 259.980000 527.340000 260.260000 ;
      RECT 0.560000 259.140000 526.780000 259.980000 ;
      RECT 0.000000 258.860000 527.340000 259.140000 ;
      RECT 0.560000 258.020000 526.780000 258.860000 ;
      RECT 0.000000 257.740000 527.340000 258.020000 ;
      RECT 0.560000 256.900000 526.780000 257.740000 ;
      RECT 0.000000 256.620000 527.340000 256.900000 ;
      RECT 0.560000 255.780000 526.780000 256.620000 ;
      RECT 0.000000 255.500000 527.340000 255.780000 ;
      RECT 0.560000 254.660000 526.780000 255.500000 ;
      RECT 0.000000 254.380000 527.340000 254.660000 ;
      RECT 0.560000 253.540000 526.780000 254.380000 ;
      RECT 0.000000 253.260000 527.340000 253.540000 ;
      RECT 0.560000 252.420000 526.780000 253.260000 ;
      RECT 0.000000 252.140000 527.340000 252.420000 ;
      RECT 0.560000 251.300000 526.780000 252.140000 ;
      RECT 0.000000 251.020000 527.340000 251.300000 ;
      RECT 0.560000 250.180000 527.340000 251.020000 ;
      RECT 0.000000 0.000000 527.340000 250.180000 ;
    LAYER Metal6 ;
      RECT 275.900000 518.220000 527.340000 519.120000 ;
      RECT 273.920000 518.220000 274.540000 519.120000 ;
      RECT 271.940000 518.220000 272.560000 519.120000 ;
      RECT 269.960000 518.220000 270.580000 519.120000 ;
      RECT 267.980000 518.220000 268.600000 519.120000 ;
      RECT 266.000000 518.220000 266.620000 519.120000 ;
      RECT 264.020000 518.220000 264.640000 519.120000 ;
      RECT 262.040000 518.220000 262.660000 519.120000 ;
      RECT 260.060000 518.220000 260.680000 519.120000 ;
      RECT 258.080000 518.220000 258.700000 519.120000 ;
      RECT 256.100000 518.220000 256.720000 519.120000 ;
      RECT 254.120000 518.220000 254.740000 519.120000 ;
      RECT 252.140000 518.220000 252.760000 519.120000 ;
      RECT 0.000000 518.220000 250.780000 519.120000 ;
      RECT 0.000000 0.900000 527.340000 518.220000 ;
      RECT 275.900000 0.000000 527.340000 0.900000 ;
      RECT 273.920000 0.000000 274.540000 0.900000 ;
      RECT 271.940000 0.000000 272.560000 0.900000 ;
      RECT 269.960000 0.000000 270.580000 0.900000 ;
      RECT 267.980000 0.000000 268.600000 0.900000 ;
      RECT 266.000000 0.000000 266.620000 0.900000 ;
      RECT 264.020000 0.000000 264.640000 0.900000 ;
      RECT 262.040000 0.000000 262.660000 0.900000 ;
      RECT 260.060000 0.000000 260.680000 0.900000 ;
      RECT 258.080000 0.000000 258.700000 0.900000 ;
      RECT 256.100000 0.000000 256.720000 0.900000 ;
      RECT 254.120000 0.000000 254.740000 0.900000 ;
      RECT 252.140000 0.000000 252.760000 0.900000 ;
      RECT 0.000000 0.000000 250.780000 0.900000 ;
  END
END Single_Cycle_Core

END LIBRARY
